VERSION 5.7 ;
  NOWIREEXTENSIONATPIN ON ;
  DIVIDERCHAR "/" ;
  BUSBITCHARS "[]" ;
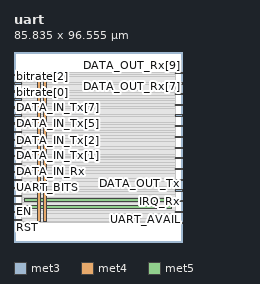
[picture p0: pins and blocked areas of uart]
MACRO uart
  CLASS BLOCK ;
  FOREIGN uart ;
  ORIGIN 0.000 0.000 ;
  SIZE 85.835 BY 96.555 ;
  PIN DATA_IN_Rx
    DIRECTION INPUT ;
    USE SIGNAL ;
    ANTENNAGATEAREA 0.159000 ;
    PORT
      LAYER met3 ;
        RECT 0.000 35.400 4.000 36.000 ;
    END
  END DATA_IN_Rx
  PIN DATA_IN_Tx[0]
    DIRECTION INPUT ;
    USE SIGNAL ;
    ANTENNAGATEAREA 0.196500 ;
    PORT
      LAYER met3 ;
        RECT 0.000 39.480 4.000 40.080 ;
    END
  END DATA_IN_Tx[0]
  PIN DATA_IN_Tx[1]
    DIRECTION INPUT ;
    USE SIGNAL ;
    ANTENNAGATEAREA 0.196500 ;
    PORT
      LAYER met3 ;
        RECT 0.000 43.560 4.000 44.160 ;
    END
  END DATA_IN_Tx[1]
  PIN DATA_IN_Tx[2]
    DIRECTION INPUT ;
    USE SIGNAL ;
    ANTENNAGATEAREA 0.196500 ;
    PORT
      LAYER met3 ;
        RECT 0.000 47.640 4.000 48.240 ;
    END
  END DATA_IN_Tx[2]
  PIN DATA_IN_Tx[3]
    DIRECTION INPUT ;
    USE SIGNAL ;
    ANTENNAGATEAREA 0.196500 ;
    PORT
      LAYER met3 ;
        RECT 0.000 51.720 4.000 52.320 ;
    END
  END DATA_IN_Tx[3]
  PIN DATA_IN_Tx[4]
    DIRECTION INPUT ;
    USE SIGNAL ;
    ANTENNAGATEAREA 0.196500 ;
    PORT
      LAYER met3 ;
        RECT 0.000 55.800 4.000 56.400 ;
    END
  END DATA_IN_Tx[4]
  PIN DATA_IN_Tx[5]
    DIRECTION INPUT ;
    USE SIGNAL ;
    ANTENNAGATEAREA 0.196500 ;
    PORT
      LAYER met3 ;
        RECT 0.000 59.880 4.000 60.480 ;
    END
  END DATA_IN_Tx[5]
  PIN DATA_IN_Tx[6]
    DIRECTION INPUT ;
    USE SIGNAL ;
    ANTENNAGATEAREA 0.196500 ;
    PORT
      LAYER met3 ;
        RECT 0.000 63.960 4.000 64.560 ;
    END
  END DATA_IN_Tx[6]
  PIN DATA_IN_Tx[7]
    DIRECTION INPUT ;
    USE SIGNAL ;
    ANTENNAGATEAREA 0.196500 ;
    PORT
      LAYER met3 ;
        RECT 0.000 68.040 4.000 68.640 ;
    END
  END DATA_IN_Tx[7]
  PIN DATA_OUT_Rx[0]
    DIRECTION OUTPUT ;
    USE SIGNAL ;
    ANTENNADIFFAREA 0.340600 ;
    PORT
      LAYER met3 ;
        RECT 81.835 36.760 85.835 37.360 ;
    END
  END DATA_OUT_Rx[0]
  PIN DATA_OUT_Rx[1]
    DIRECTION OUTPUT ;
    USE SIGNAL ;
    ANTENNADIFFAREA 0.340600 ;
    PORT
      LAYER met3 ;
        RECT 81.835 42.200 85.835 42.800 ;
    END
  END DATA_OUT_Rx[1]
  PIN DATA_OUT_Rx[2]
    DIRECTION OUTPUT ;
    USE SIGNAL ;
    ANTENNADIFFAREA 0.340600 ;
    PORT
      LAYER met3 ;
        RECT 81.835 47.640 85.835 48.240 ;
    END
  END DATA_OUT_Rx[2]
  PIN DATA_OUT_Rx[3]
    DIRECTION OUTPUT ;
    USE SIGNAL ;
    ANTENNADIFFAREA 0.340600 ;
    PORT
      LAYER met3 ;
        RECT 81.835 53.080 85.835 53.680 ;
    END
  END DATA_OUT_Rx[3]
  PIN DATA_OUT_Rx[4]
    DIRECTION OUTPUT ;
    USE SIGNAL ;
    ANTENNADIFFAREA 0.340600 ;
    PORT
      LAYER met3 ;
        RECT 81.835 58.520 85.835 59.120 ;
    END
  END DATA_OUT_Rx[4]
  PIN DATA_OUT_Rx[5]
    DIRECTION OUTPUT ;
    USE SIGNAL ;
    ANTENNADIFFAREA 0.340600 ;
    PORT
      LAYER met3 ;
        RECT 81.835 63.960 85.835 64.560 ;
    END
  END DATA_OUT_Rx[5]
  PIN DATA_OUT_Rx[6]
    DIRECTION OUTPUT ;
    USE SIGNAL ;
    ANTENNADIFFAREA 0.340600 ;
    PORT
      LAYER met3 ;
        RECT 81.835 69.400 85.835 70.000 ;
    END
  END DATA_OUT_Rx[6]
  PIN DATA_OUT_Rx[7]
    DIRECTION OUTPUT ;
    USE SIGNAL ;
    ANTENNADIFFAREA 0.340600 ;
    PORT
      LAYER met3 ;
        RECT 81.835 74.840 85.835 75.440 ;
    END
  END DATA_OUT_Rx[7]
  PIN DATA_OUT_Rx[8]
    DIRECTION OUTPUT ;
    USE SIGNAL ;
    ANTENNADIFFAREA 0.445500 ;
    PORT
      LAYER met3 ;
        RECT 81.835 80.280 85.835 80.880 ;
    END
  END DATA_OUT_Rx[8]
  PIN DATA_OUT_Rx[9]
    DIRECTION OUTPUT ;
    USE SIGNAL ;
    ANTENNADIFFAREA 0.445500 ;
    PORT
      LAYER met3 ;
        RECT 81.835 85.720 85.835 86.320 ;
    END
  END DATA_OUT_Rx[9]
  PIN DATA_OUT_Tx
    DIRECTION OUTPUT ;
    USE SIGNAL ;
    ANTENNADIFFAREA 0.340600 ;
    PORT
      LAYER met3 ;
        RECT 81.835 25.880 85.835 26.480 ;
    END
  END DATA_OUT_Tx
  PIN EN
    DIRECTION INPUT ;
    USE SIGNAL ;
    ANTENNAGATEAREA 0.196500 ;
    PORT
      LAYER met3 ;
        RECT 0.000 15.000 4.000 15.600 ;
    END
  END EN
  PIN IRQ_Rx
    DIRECTION OUTPUT ;
    USE SIGNAL ;
    ANTENNADIFFAREA 0.340600 ;
    PORT
      LAYER met3 ;
        RECT 81.835 20.440 85.835 21.040 ;
    END
  END IRQ_Rx
  PIN IRQ_Tx
    DIRECTION OUTPUT ;
    USE SIGNAL ;
    ANTENNADIFFAREA 0.340600 ;
    PORT
      LAYER met3 ;
        RECT 81.835 31.320 85.835 31.920 ;
    END
  END IRQ_Tx
  PIN RST
    DIRECTION INPUT ;
    USE SIGNAL ;
    ANTENNAGATEAREA 0.990000 ;
    PORT
      LAYER met3 ;
        RECT 0.000 10.920 4.000 11.520 ;
    END
  END RST
  PIN UART_AVAIL
    DIRECTION OUTPUT ;
    USE SIGNAL ;
    ANTENNADIFFAREA 0.340600 ;
    PORT
      LAYER met3 ;
        RECT 81.835 15.000 85.835 15.600 ;
    END
  END UART_AVAIL
  PIN UART_BITS
    DIRECTION INPUT ;
    USE SIGNAL ;
    ANTENNAGATEAREA 0.196500 ;
    PORT
      LAYER met3 ;
        RECT 0.000 27.240 4.000 27.840 ;
    END
  END UART_BITS
  PIN UART_PARITY
    DIRECTION INPUT ;
    USE SIGNAL ;
    ANTENNAGATEAREA 0.196500 ;
    PORT
      LAYER met3 ;
        RECT 0.000 31.320 4.000 31.920 ;
    END
  END UART_PARITY
  PIN UART_WRITE
    DIRECTION INPUT ;
    USE SIGNAL ;
    ANTENNAGATEAREA 0.196500 ;
    PORT
      LAYER met3 ;
        RECT 0.000 23.160 4.000 23.760 ;
    END
  END UART_WRITE
  PIN VGND
    DIRECTION INOUT ;
    USE GROUND ;
    PORT
      LAYER met4 ;
        RECT 15.020 10.640 16.620 84.560 ;
    END
    PORT
      LAYER met5 ;
        RECT 5.280 20.380 80.280 21.980 ;
    END
  END VGND
  PIN VPWR
    DIRECTION INOUT ;
    USE POWER ;
    PORT
      LAYER met4 ;
        RECT 11.720 10.640 13.320 84.560 ;
    END
    PORT
      LAYER met5 ;
        RECT 5.280 17.080 80.280 18.680 ;
    END
  END VPWR
  PIN bitrate[0]
    DIRECTION INPUT ;
    USE SIGNAL ;
    ANTENNAGATEAREA 0.247500 ;
    PORT
      LAYER met3 ;
        RECT 0.000 72.120 4.000 72.720 ;
    END
  END bitrate[0]
  PIN bitrate[1]
    DIRECTION INPUT ;
    USE SIGNAL ;
    ANTENNAGATEAREA 0.247500 ;
    PORT
      LAYER met3 ;
        RECT 0.000 76.200 4.000 76.800 ;
    END
  END bitrate[1]
  PIN bitrate[2]
    DIRECTION INPUT ;
    USE SIGNAL ;
    ANTENNAGATEAREA 0.213000 ;
    PORT
      LAYER met3 ;
        RECT 0.000 80.280 4.000 80.880 ;
    END
  END bitrate[2]
  PIN bitrate[3]
    DIRECTION INPUT ;
    USE SIGNAL ;
    ANTENNAGATEAREA 0.159000 ;
    PORT
      LAYER met3 ;
        RECT 0.000 84.360 4.000 84.960 ;
    END
  END bitrate[3]
  PIN clk_CPU
    DIRECTION INPUT ;
    USE SIGNAL ;
    ANTENNAGATEAREA 0.852000 ;
    PORT
      LAYER met3 ;
        RECT 0.000 19.080 4.000 19.680 ;
    END
  END clk_CPU
  PIN uart_clock
    DIRECTION OUTPUT ;
    USE SIGNAL ;
    ANTENNADIFFAREA 0.340600 ;
    PORT
      LAYER met3 ;
        RECT 81.835 9.560 85.835 10.160 ;
    END
  END uart_clock
  OBS
      LAYER nwell ;
        RECT 5.330 10.795 80.230 84.510 ;
      LAYER li1 ;
        RECT 5.520 10.795 80.040 84.405 ;
      LAYER met1 ;
        RECT 4.210 10.640 80.040 84.560 ;
      LAYER met2 ;
        RECT 4.230 9.675 78.570 86.205 ;
      LAYER met3 ;
        RECT 3.950 85.360 81.435 86.185 ;
        RECT 4.400 85.320 81.435 85.360 ;
        RECT 4.400 83.960 81.835 85.320 ;
        RECT 3.950 81.280 81.835 83.960 ;
        RECT 4.400 79.880 81.435 81.280 ;
        RECT 3.950 77.200 81.835 79.880 ;
        RECT 4.400 75.840 81.835 77.200 ;
        RECT 4.400 75.800 81.435 75.840 ;
        RECT 3.950 74.440 81.435 75.800 ;
        RECT 3.950 73.120 81.835 74.440 ;
        RECT 4.400 71.720 81.835 73.120 ;
        RECT 3.950 70.400 81.835 71.720 ;
        RECT 3.950 69.040 81.435 70.400 ;
        RECT 4.400 69.000 81.435 69.040 ;
        RECT 4.400 67.640 81.835 69.000 ;
        RECT 3.950 64.960 81.835 67.640 ;
        RECT 4.400 63.560 81.435 64.960 ;
        RECT 3.950 60.880 81.835 63.560 ;
        RECT 4.400 59.520 81.835 60.880 ;
        RECT 4.400 59.480 81.435 59.520 ;
        RECT 3.950 58.120 81.435 59.480 ;
        RECT 3.950 56.800 81.835 58.120 ;
        RECT 4.400 55.400 81.835 56.800 ;
        RECT 3.950 54.080 81.835 55.400 ;
        RECT 3.950 52.720 81.435 54.080 ;
        RECT 4.400 52.680 81.435 52.720 ;
        RECT 4.400 51.320 81.835 52.680 ;
        RECT 3.950 48.640 81.835 51.320 ;
        RECT 4.400 47.240 81.435 48.640 ;
        RECT 3.950 44.560 81.835 47.240 ;
        RECT 4.400 43.200 81.835 44.560 ;
        RECT 4.400 43.160 81.435 43.200 ;
        RECT 3.950 41.800 81.435 43.160 ;
        RECT 3.950 40.480 81.835 41.800 ;
        RECT 4.400 39.080 81.835 40.480 ;
        RECT 3.950 37.760 81.835 39.080 ;
        RECT 3.950 36.400 81.435 37.760 ;
        RECT 4.400 36.360 81.435 36.400 ;
        RECT 4.400 35.000 81.835 36.360 ;
        RECT 3.950 32.320 81.835 35.000 ;
        RECT 4.400 30.920 81.435 32.320 ;
        RECT 3.950 28.240 81.835 30.920 ;
        RECT 4.400 26.880 81.835 28.240 ;
        RECT 4.400 26.840 81.435 26.880 ;
        RECT 3.950 25.480 81.435 26.840 ;
        RECT 3.950 24.160 81.835 25.480 ;
        RECT 4.400 22.760 81.835 24.160 ;
        RECT 3.950 21.440 81.835 22.760 ;
        RECT 3.950 20.080 81.435 21.440 ;
        RECT 4.400 20.040 81.435 20.080 ;
        RECT 4.400 18.680 81.835 20.040 ;
        RECT 3.950 16.000 81.835 18.680 ;
        RECT 4.400 14.600 81.435 16.000 ;
        RECT 3.950 11.920 81.835 14.600 ;
        RECT 4.400 10.560 81.835 11.920 ;
        RECT 4.400 10.520 81.435 10.560 ;
        RECT 3.950 9.695 81.435 10.520 ;
      LAYER met4 ;
        RECT 3.975 15.135 4.305 53.545 ;
  END
END uart
END LIBRARY

